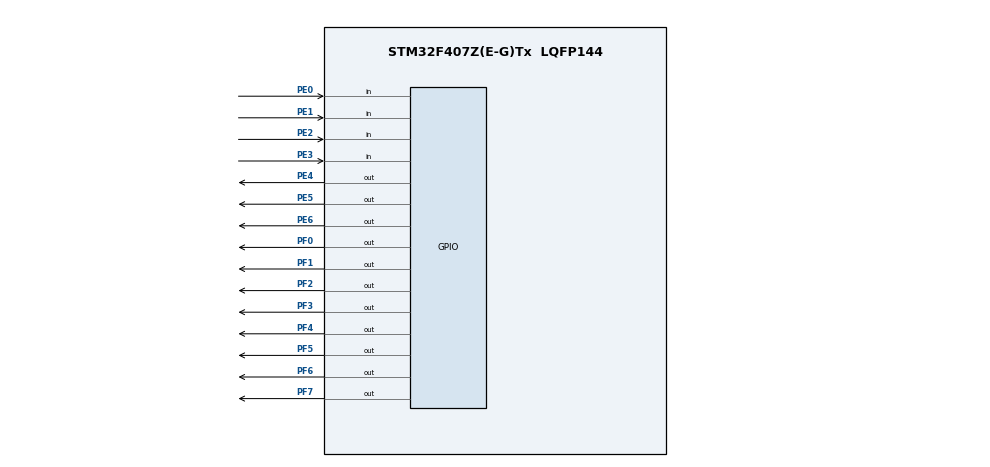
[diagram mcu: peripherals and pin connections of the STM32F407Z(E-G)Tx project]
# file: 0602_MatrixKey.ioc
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Mcu.Family=STM32F4
Mcu.Name=STM32F407Z(E-G)Tx
Mcu.Package=LQFP144
NVIC.PriorityGroup=NVIC_PRIORITYGROUP_4
PE0.GPIO_PuPd=GPIO_PULLUP
PE0.Signal=GPIO_Input
PE1.GPIO_PuPd=GPIO_PULLUP
PE1.Signal=GPIO_Input
PE2.GPIO_PuPd=GPIO_PULLUP
PE2.Signal=GPIO_Input
PE3.GPIO_PuPd=GPIO_PULLUP
PE3.Signal=GPIO_Input
PE4.GPIO_ModeDefaultOutputPP=GPIO_MODE_OUTPUT_PP
PE4.GPIO_PuPd=GPIO_NOPULL
PE4.PinState=GPIO_PIN_SET
PE4.Signal=GPIO_Output
PE5.PinState=GPIO_PIN_SET
PE5.Signal=GPIO_Output
PE6.PinState=GPIO_PIN_SET
PE6.Signal=GPIO_Output
PF0.PinState=GPIO_PIN_SET
PF0.Signal=GPIO_Output
PF1.PinState=GPIO_PIN_SET
PF1.Signal=GPIO_Output
PF2.PinState=GPIO_PIN_SET
PF2.Signal=GPIO_Output
PF3.PinState=GPIO_PIN_SET
PF3.Signal=GPIO_Output
PF4.PinState=GPIO_PIN_SET
PF4.Signal=GPIO_Output
PF5.PinState=GPIO_PIN_SET
PF5.Signal=GPIO_Output
PF6.PinState=GPIO_PIN_SET
PF6.Signal=GPIO_Output
PF7.PinState=GPIO_PIN_SET
PF7.Signal=GPIO_Output
ProjectManager.HeapSize=0x200
ProjectManager.StackSize=0x400
ProjectManager.TargetToolchain=MDK-ARM V5
RCC.AHBFreq_Value=16000000
RCC.APB1Freq_Value=16000000
RCC.APB2Freq_Value=16000000
RCC.CortexFreq_Value=16000000
RCC.HSE_VALUE=25000000
RCC.HSI_VALUE=16000000
RCC.LSE_VALUE=32768
RCC.SYSCLKFreq_VALUE=16000000
RCC.VCOOutputFreq_Value=192000000
board=custom

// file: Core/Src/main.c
/* USER CODE BEGIN Header */
/**
  ******************************************************************************
  * @file           : main.c
  * @brief          : Main program body (3x4 Matrix Keypad Scan)
  ******************************************************************************
  * @attention
  *
  * Copyright (c) 2024 STMicroelectronics.
  * All rights reserved.
  *
  * This software is licensed under terms that can be found in the LICENSE file
  * in the root directory of this software component.
  * If no LICENSE file comes with this software, it is provided AS-IS.
  *
  ******************************************************************************
  */
/* USER CODE END Header */
#include "main.h"

void SystemClock_Config(void);
static void MX_GPIO_Init(void);

int main(void)
{
  /* USER CODE BEGIN 1 */
  // ?????????
  uint16_t i, KeyVal = 0;
  // ????????,?????? (2???3?, 0???1?, 1???2?)
  uint8_t PreLine[3] = {2, 0, 1};
  /* USER CODE END 1 */

  /* MCU Configuration--------------------------------------------------------*/

  /* Reset of all peripherals, Initializes the Flash interface and the Systick. */
  HAL_Init();

  /* Configure the system clock */
  SystemClock_Config();

  /* Initialize all configured peripherals */
  MX_GPIO_Init();

  /* Infinite loop */
  while (1)
  {

    /* USER CODE BEGIN 3 */
    for(i = 0; i < 3; i++)
    {
        // 1. ?????? (PE0~PE3)?0x0F?????4?
        // ????0x0F (?1111),????????;??????????
        if((GPIOE->IDR & 0x0F) != 0x0F)
        {
            HAL_Delay(16); // ????,???16ms

            // 2. ????????,????????
            if((GPIOE->IDR & 0x0F) != 0x0F)
            {
                // 3. ??????????????,????? (1~12)
                // ??:??????????????????
                switch(GPIOE->IDR & 0x0F)
                {
                    case 0x0E: KeyVal = 4 * PreLine[i] + 1; break; // 1110,?1?
                    case 0x0D: KeyVal = 4 * PreLine[i] + 2; break; // 1101,?2?
                    case 0x0B: KeyVal = 4 * PreLine[i] + 3; break; // 1011,?3?
                    case 0x07: KeyVal = 4 * PreLine[i] + 4; break; // 0111,?4?
                    default: break;
                }

                // 4. ??????8421BCD???PF0~PF7?LED???
                // KeyVal/10 ???,KeyVal%10 ???,???????(?????LED)
                GPIOF->ODR = ~( ((KeyVal / 10) << 4) + (KeyVal % 10) );
            }
        }

        // 5. ????????????(???????)
        // i=0?,??PE4;i=1?,??PE5;i=2?,??PE6
        GPIOE->ODR = ~(1 << (i + 4));
    }
    /* USER CODE END 3 */
  }

  /**
  * @brief System Clock Configuration
  * @retval None
  */
}

void SystemClock_Config(void)
{
  RCC_OscInitTypeDef RCC_OscInitStruct = {0};
  RCC_ClkInitTypeDef RCC_ClkInitStruct = {0};

  /** Configure the main internal regulator output voltage
  */
  __HAL_RCC_PWR_CLK_ENABLE();
  __HAL_PWR_VOLTAGESCALING_CONFIG(PWR_REGULATOR_VOLTAGE_SCALE1);

  /** Initializes the RCC Oscillators according to the specified parameters
  * in the RCC_OscInitTypeDef structure.
  */
  RCC_OscInitStruct.OscillatorType = RCC_OSCILLATORTYPE_HSI;
  RCC_OscInitStruct.HSIState = RCC_HSI_ON;
  RCC_OscInitStruct.HSICalibrationValue = RCC_HSICALIBRATION_DEFAULT;
  RCC_OscInitStruct.PLL.PLLState = RCC_PLL_ON;
  RCC_OscInitStruct.PLL.PLLSource = RCC_PLLSOURCE_HSI;
  RCC_OscInitStruct.PLL.PLLM = 8;
  RCC_OscInitStruct.PLL.PLLN = 168;
  RCC_OscInitStruct.PLL.PLLP = RCC_PLLP_DIV2;
  RCC_OscInitStruct.PLL.PLLQ = 4;
  if (HAL_RCC_OscConfig(&RCC_OscInitStruct) != HAL_OK)
  {
    Error_Handler();
  }

  /** Initializes the CPU, AHB and APB buses clocks
  */
  RCC_ClkInitStruct.ClockType = RCC_CLOCKTYPE_HCLK|RCC_CLOCKTYPE_SYSCLK
                              |RCC_CLOCKTYPE_PCLK1|RCC_CLOCKTYPE_PCLK2;
  RCC_ClkInitStruct.SYSCLKSource = RCC_SYSCLKSOURCE_PLLCLK;
  RCC_ClkInitStruct.AHBCLKDivider = RCC_SYSCLK_DIV1;
  RCC_ClkInitStruct.APB1CLKDivider = RCC_HCLK_DIV4;
  RCC_ClkInitStruct.APB2CLKDivider = RCC_HCLK_DIV2;

  if (HAL_RCC_ClockConfig(&RCC_ClkInitStruct, FLASH_LATENCY_5) != HAL_OK)
  {
    Error_Handler();
  }
}

static void MX_GPIO_Init(void)
{
  GPIO_InitTypeDef GPIO_InitStruct = {0};

  /* GPIO Ports Clock Enable */
  __HAL_RCC_GPIOE_CLK_ENABLE();
  __HAL_RCC_GPIOF_CLK_ENABLE();

  /*Configure GPIO pin Output Level */
  HAL_GPIO_WritePin(GPIOF, GPIO_PIN_0|GPIO_PIN_1|GPIO_PIN_2|GPIO_PIN_3
                          |GPIO_PIN_4|GPIO_PIN_5|GPIO_PIN_6|GPIO_PIN_7, GPIO_PIN_SET);

  /*Configure GPIO pin Output Level */
  HAL_GPIO_WritePin(GPIOE, GPIO_PIN_4|GPIO_PIN_5|GPIO_PIN_6, GPIO_PIN_SET);

  /*Configure GPIO pins : PF0 PF1 PF2 PF3 PF4 PF5 PF6 PF7 */
  GPIO_InitStruct.Pin = GPIO_PIN_0|GPIO_PIN_1|GPIO_PIN_2|GPIO_PIN_3
                          |GPIO_PIN_4|GPIO_PIN_5|GPIO_PIN_6|GPIO_PIN_7;
  GPIO_InitStruct.Mode = GPIO_MODE_OUTPUT_PP;
  GPIO_InitStruct.Pull = GPIO_NOPULL;
  GPIO_InitStruct.Speed = GPIO_SPEED_FREQ_LOW;
  HAL_GPIO_Init(GPIOF, &GPIO_InitStruct);

  /*Configure GPIO pins : PE0 PE1 PE2 PE3 */
  GPIO_InitStruct.Pin = GPIO_PIN_0|GPIO_PIN_1|GPIO_PIN_2|GPIO_PIN_3;
  GPIO_InitStruct.Mode = GPIO_MODE_INPUT;
  GPIO_InitStruct.Pull = GPIO_PULLUP;
  HAL_GPIO_Init(GPIOE, &GPIO_InitStruct);

  /*Configure GPIO pins : PE4 PE5 PE6 */
  GPIO_InitStruct.Pin = GPIO_PIN_4|GPIO_PIN_5|GPIO_PIN_6;
  GPIO_InitStruct.Mode = GPIO_MODE_OUTPUT_PP;
  GPIO_InitStruct.Pull = GPIO_NOPULL;
  GPIO_InitStruct.Speed = GPIO_SPEED_FREQ_LOW;
  HAL_GPIO_Init(GPIOE, &GPIO_InitStruct);

}

void Error_Handler(void)
{
  __disable_irq();
  while (1)
  {
  }
}
